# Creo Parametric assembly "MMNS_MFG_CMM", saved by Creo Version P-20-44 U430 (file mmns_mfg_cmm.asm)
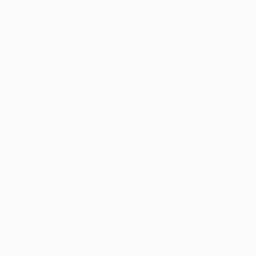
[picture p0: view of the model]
Units: millimeter Newton Second (mmNs); MM, TONNE, SECS

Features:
  1. datum plane "CMM_RIGHT"
  2. datum plane "CMM_TOP"
  3. datum plane "CMM_FRONT"
  4. coordinate system

Other named items: CMM_DEF_CSYS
